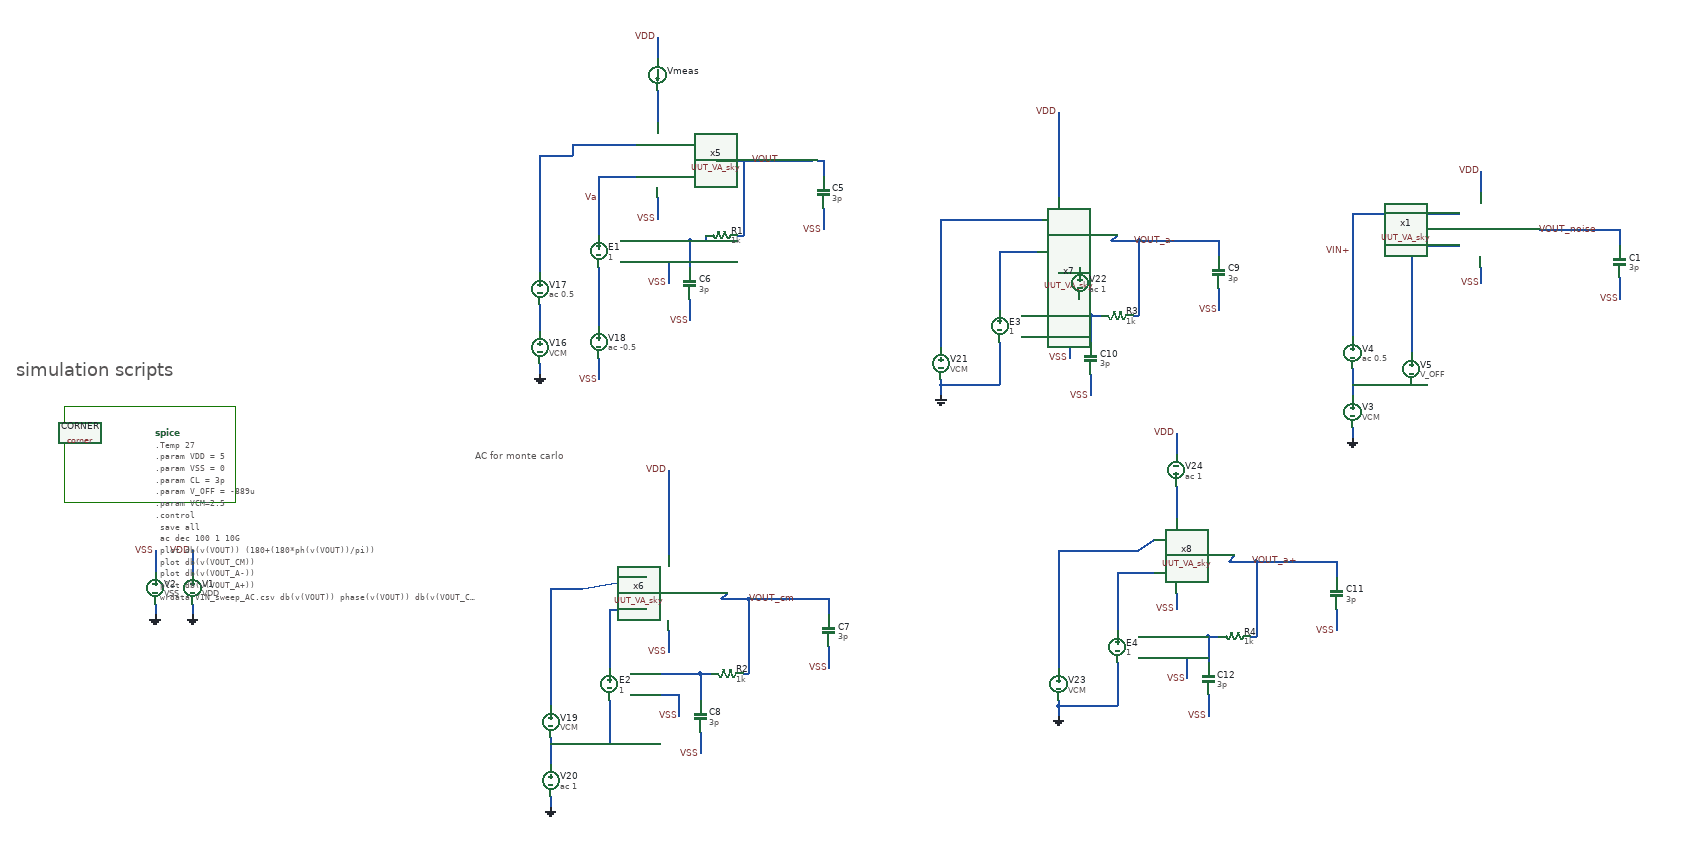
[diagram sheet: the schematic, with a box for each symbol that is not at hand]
v {xschem version=3.4.6 file_version=1.2}
G {}
K {}
V {}
S {}
E {}
L 4 -1660 -1300 -1660 -1140 {}
L 4 -1660 -1140 -1340 -1140 {}
L 4 -1340 -1320 -1340 -1140 {}
L 4 -1660 -1320 -1340 -1320 {}
L 4 -1660 -1320 -1660 -1300 {}
T {simulation scripts} -1750 -1400 0 0 1 1 {}
T {AC for monte carlo} -890 -1240 0 0 0.4 0.4 {}
N -1420 -950 -1420 -930 {
lab=GND}
N -1420 -1050 -1420 -1010 {
lab=VDD}
N -1490 -950 -1490 -930 {
lab=GND}
N -1490 -1050 -1490 -1010 {
lab=VSS}
N -550 -1710 -550 -1670 {
lab=VSS}
N -770 -1510 -770 -1460 {
lab=#net1}
N -550 -2010 -550 -1970 {
lab=VDD}
N -440 -1780 -390 -1780 {
lab=VOUT}
N -550 -1910 -550 -1850 {
lab=#net2}
N -240 -1690 -240 -1650 {
lab=VSS}
N -400 -1780 -260 -1780 {lab=VOUT}
N -250 -1780 -240 -1780 {lab=VOUT}
N -240 -1780 -240 -1750 {lab=VOUT}
N -770 -1790 -710 -1790 {lab=#net3}
N -770 -1400 -770 -1380 {lab=GND}
N -770 -1790 -770 -1570 {lab=#net3}
N -660 -1690 -660 -1640 {lab=Va}
N -660 -1750 -660 -1690 {lab=Va}
N -660 -1410 -660 -1370 {
lab=VSS}
N -660 -1580 -660 -1550 {lab=#net4}
N -390 -1780 -390 -1640 {lab=VOUT}
N -530 -1590 -530 -1550 {
lab=VSS}
N -620 -1590 -530 -1590 {lab=VSS}
N -660 -1500 -660 -1470 {lab=#net4}
N -660 -1550 -660 -1500 {lab=#net4}
N -400 -1640 -390 -1640 {lab=VOUT}
N -490 -1520 -490 -1480 {
lab=VSS}
N -490 -1630 -490 -1580 {lab=#net5}
N -490 -1630 -470 -1630 {lab=#net5}
N -620 -1630 -490 -1630 {lab=#net5}
N -530 -900 -530 -860 {
lab=VSS}
N -750 -700 -750 -650 {
lab=#net6}
N -530 -1200 -530 -1160 {
lab=VDD}
N -430 -960 -380 -960 {
lab=VOUT_cm}
N -530 -1100 -530 -1040 {
lab=VDD}
N -230 -870 -230 -830 {
lab=VSS}
N -240 -960 -230 -960 {lab=VOUT_cm}
N -230 -960 -230 -930 {lab=VOUT_cm}
N -750 -980 -690 -980 {lab=#net7}
N -750 -590 -750 -570 {lab=GND}
N -750 -980 -750 -760 {lab=#net7}
N -640 -880 -640 -830 {lab=#net8}
N -640 -940 -640 -880 {lab=#net8}
N -380 -960 -380 -820 {lab=VOUT_cm}
N -510 -780 -510 -740 {
lab=VSS}
N -600 -780 -510 -780 {lab=VSS}
N -390 -820 -380 -820 {lab=VOUT_cm}
N -470 -710 -470 -670 {
lab=VSS}
N -470 -820 -470 -770 {lab=#net9}
N -470 -820 -450 -820 {lab=#net9}
N -600 -820 -470 -820 {lab=#net9}
N -640 -770 -640 -690 {lab=#net6}
N -750 -690 -640 -690 {lab=#net6}
N -380 -960 -240 -960 {lab=VOUT_cm}
N 200 -1870 200 -1830 {
lab=VDD}
N 300 -1630 350 -1630 {
lab=VOUT_a-}
N 200 -1770 200 -1710 {
lab=VDD}
N 80 -1670 170 -1670 {lab=#net10}
N 500 -1540 500 -1500 {
lab=VSS}
N 490 -1630 500 -1630 {lab=VOUT_a-}
N 500 -1630 500 -1600 {lab=VOUT_a-}
N -20 -1360 -20 -1340 {lab=GND}
N -20 -1650 -20 -1430 {lab=#net10}
N 90 -1550 90 -1500 {lab=#net11}
N 90 -1610 90 -1550 {lab=#net11}
N 350 -1630 350 -1490 {lab=VOUT_a-}
N 220 -1450 220 -1410 {
lab=VSS}
N 130 -1450 220 -1450 {lab=VSS}
N 340 -1490 350 -1490 {lab=VOUT_a-}
N 260 -1380 260 -1340 {
lab=VSS}
N 260 -1490 260 -1440 {lab=#net12}
N 260 -1490 280 -1490 {lab=#net12}
N 130 -1490 260 -1490 {lab=#net12}
N 90 -1440 90 -1360 {lab=GND}
N -20 -1360 90 -1360 {lab=GND}
N 350 -1630 490 -1630 {lab=VOUT_a-}
N -20 -1370 -20 -1360 {lab=GND}
N 240 -1600 240 -1580 {lab=#net13}
N 240 -1520 240 -1510 {lab=VSS}
N 420 -1270 420 -1230 {
lab=VDD}
N 520 -1030 570 -1030 {
lab=VOUT_a+}
N 420 -1170 420 -1110 {
lab=#net14}
N 260 -1050 350 -1050 {lab=#net15}
N 720 -940 720 -900 {
lab=VSS}
N 710 -1030 720 -1030 {lab=VOUT_a+}
N 720 -1030 720 -1000 {lab=VOUT_a+}
N 200 -1050 260 -1050 {lab=#net15}
N 310 -1010 360 -1010 {lab=#net16}
N 200 -760 200 -740 {lab=GND}
N 200 -1050 200 -830 {lab=#net15}
N 310 -950 310 -900 {lab=#net16}
N 310 -1010 310 -950 {lab=#net16}
N 570 -1030 570 -890 {lab=VOUT_a+}
N 440 -850 440 -810 {
lab=VSS}
N 350 -850 440 -850 {lab=VSS}
N 560 -890 570 -890 {lab=VOUT_a+}
N 480 -780 480 -740 {
lab=VSS}
N 480 -890 480 -840 {lab=#net17}
N 480 -890 500 -890 {lab=#net17}
N 350 -890 480 -890 {lab=#net17}
N 310 -840 310 -760 {lab=GND}
N 200 -760 310 -760 {lab=GND}
N 570 -1030 710 -1030 {lab=VOUT_a+}
N 200 -770 200 -760 {lab=GND}
N 420 -970 420 -950 {lab=VSS}
N 420 -950 420 -940 {lab=VSS}
N 200 -1830 200 -1770 {lab=VDD}
N -530 -1160 -530 -1100 {lab=VDD}
N -660 -1750 -590 -1750 {lab=Va}
N -710 -1810 -590 -1810 {lab=#net3}
N -710 -1810 -710 -1790 {lab=#net3}
N -460 -1640 -460 -1630 {lab=#net5}
N -470 -1630 -460 -1630 {lab=#net5}
N -20 -1670 80 -1670 {lab=#net10}
N -20 -1670 -20 -1650 {lab=#net10}
N 90 -1610 160 -1610 {lab=#net11}
N 200 -1570 240 -1600 {lab=#net13}
N 300 -1630 310 -1640 {lab=VOUT_a-}
N 520 -1030 530 -1040 {lab=VOUT_a+}
N 350 -1050 380 -1070 {lab=#net15}
N 360 -1010 380 -1010 {lab=#net16}
N -430 -960 -420 -970 {lab=VOUT_cm}
N -640 -940 -570 -940 {lab=#net8}
N -690 -980 -570 -1000 {lab=#net7}
N 750 -1390 750 -1340 {
lab=#net18}
N 750 -1280 750 -1260 {lab=GND}
N 750 -1670 750 -1450 {lab=VIN+}
N 750 -1680 750 -1670 {lab=VIN+}
N 750 -1680 950 -1680 {lab=VIN+}
N 750 -1360 860 -1360 {lab=#net18}
N 860 -1620 860 -1420 {lab=#net19}
N 860 -1620 950 -1620 {lab=#net19}
N 990 -1580 990 -1560 {lab=VSS}
N 990 -1560 990 -1550 {lab=VSS}
N 990 -1760 990 -1720 {
lab=VDD}
N 1250 -1560 1250 -1520 {
lab=VSS}
N 1240 -1650 1250 -1650 {lab=VOUT_noise}
N 1250 -1650 1250 -1620 {lab=VOUT_noise}
N 1100 -1650 1240 -1650 {lab=VOUT_noise}
C {devices/lab_pin.sym} -1420 -1050 0 0 {name=p6 sig_type=std_logic lab=VDD}
C {devices/vsource.sym} -1420 -980 0 0 {name=V1 value="VDD"

}
C {devices/gnd.sym} -1420 -930 0 0 {name=l3 lab=GND}
C {devices/vsource.sym} -1490 -980 0 0 {name=V2 value="VSS"


}
C {devices/gnd.sym} -1490 -930 0 0 {name=l1 lab=GND}
C {sky130_fd_pr/corner.sym} -1630 -1270 0 0 {name=CORNER only_toplevel=true corner=tt}
C {devices/lab_pin.sym} -1490 -1050 0 0 {name=p8 sig_type=std_logic lab=VSS
}
C {devices/code.sym} -1490 -1270 0 0 {name=spice only_toplevel=false
format="tcleval( @value )"
value="	
.Temp 27
.param VDD = 5
.param VSS = 0
.param CL = 3p
.param V_OFF = -889u
.param VCM=2.5


.control

	save all
	ac dec 100 1 10G
	plot db(v(VOUT)) (180+(180*ph(v(VOUT))/pi))
	plot db(v(VOUT_CM))
	plot db(v(VOUT_A-))
	plot db(v(VOUT_A+))	
	wrdata VIN_sweep_AC.csv db(v(VOUT)) phase(v(VOUT)) db(v(VOUT_CM)) db(v(VOUT_A-)) db(v(VOUT_A+))

	noise v(VOUT_noise,VSS) V4 dec 10 1 40000k
	print inoise_total 
	print onoise_total
	setplot noise1

	plot onoise_spectrum
	plot inoise_spectrum

.endc



"}
C {devices/lab_pin.sym} -550 -1670 0 0 {name=p23 sig_type=std_logic lab=VSS
}
C {devices/lab_pin.sym} -550 -2010 0 0 {name=p24 sig_type=std_logic lab=VDD}
C {ammeter.sym} -550 -1940 0 0 {name=Vmeas savecurrent=true}
C {Sky130A/UUT_sky/UUT_VA_sky.sym} -520 -1780 0 0 {name=x5}
C {capa.sym} -240 -1720 0 0 {name=C5
m=1
value=3p
footprint=1206
device="ceramic capacitor"}
C {devices/lab_pin.sym} -240 -1650 0 0 {name=p26 sig_type=std_logic lab=VSS
}
C {devices/vsource.sym} -770 -1430 0 0 {name=V16 value= "VCM"}
C {devices/gnd.sym} -770 -1380 0 0 {name=l7 lab=GND}
C {devices/vsource.sym} -770 -1540 0 0 {name=V17 value= "ac 0.5"}
C {devices/lab_pin.sym} 750 -1610 0 0 {name=p27 sig_type=std_logic lab=VIN+
}
C {devices/lab_pin.sym} -660 -1370 0 0 {name=p28 sig_type=std_logic lab=VSS
}
C {devices/vsource.sym} -660 -1440 0 0 {name=V18 value= "ac -0.5"}
C {vcvs.sym} -660 -1610 0 1 {name=E1 value=1}
C {devices/lab_pin.sym} -530 -1550 0 0 {name=p29 sig_type=std_logic lab=VSS
}
C {devices/lab_pin.sym} -660 -1710 0 0 {name=p30 sig_type=std_logic lab=Va
}
C {res_ac.sym} -430 -1640 1 0 {name=R1
value=1k
ac=1000000000000G
m=1}
C {capa.sym} -490 -1550 0 0 {name=C6
m=1
value=3p
footprint=1206
device="ceramic capacitor"}
C {devices/lab_pin.sym} -490 -1480 0 0 {name=p31 sig_type=std_logic lab=VSS
}
C {devices/lab_pin.sym} -530 -860 0 0 {name=p32 sig_type=std_logic lab=VSS
}
C {devices/lab_pin.sym} -530 -1200 0 0 {name=p33 sig_type=std_logic lab=VDD}
C {Sky130A/UUT_sky/UUT_VA_sky.sym} -500 -970 0 0 {name=x6}
C {capa.sym} -230 -900 0 0 {name=C7
m=1
value=3p
footprint=1206
device="ceramic capacitor"}
C {devices/lab_pin.sym} -230 -830 0 0 {name=p34 sig_type=std_logic lab=VSS
}
C {devices/vsource.sym} -750 -730 0 0 {name=V19 value= "VCM"}
C {devices/gnd.sym} -750 -570 0 0 {name=l8 lab=GND}
C {devices/vsource.sym} -750 -620 0 0 {name=V20 value= "ac 1"}
C {vcvs.sym} -640 -800 0 1 {name=E2 value=1}
C {devices/lab_pin.sym} -510 -740 0 0 {name=p35 sig_type=std_logic lab=VSS
}
C {res_ac.sym} -420 -820 1 0 {name=R2
value=1k
ac=1000000000000G
m=1}
C {capa.sym} -470 -740 0 0 {name=C8
m=1
value=3p
footprint=1206
device="ceramic capacitor"}
C {devices/lab_pin.sym} -470 -670 0 0 {name=p36 sig_type=std_logic lab=VSS
}
C {devices/lab_pin.sym} 240 -1510 0 0 {name=p38 sig_type=std_logic lab=VSS
}
C {devices/lab_pin.sym} 200 -1870 0 0 {name=p39 sig_type=std_logic lab=VDD}
C {Sky130A/UUT_sky/UUT_VA_sky.sym} 230 -1640 0 0 {name=x7}
C {capa.sym} 500 -1570 0 0 {name=C9
m=1
value=3p
footprint=1206
device="ceramic capacitor"}
C {devices/lab_pin.sym} 500 -1500 0 0 {name=p40 sig_type=std_logic lab=VSS
}
C {devices/vsource.sym} -20 -1400 0 0 {name=V21 value= "VCM"}
C {devices/gnd.sym} -20 -1340 0 0 {name=l9 lab=GND}
C {vcvs.sym} 90 -1470 0 1 {name=E3 value=1}
C {devices/lab_pin.sym} 220 -1410 0 0 {name=p41 sig_type=std_logic lab=VSS
}
C {res_ac.sym} 310 -1490 1 0 {name=R3
value=1k
ac=1000000000000G
m=1}
C {capa.sym} 260 -1410 0 0 {name=C10
m=1
value=3p
footprint=1206
device="ceramic capacitor"}
C {devices/lab_pin.sym} 260 -1340 0 0 {name=p42 sig_type=std_logic lab=VSS
}
C {devices/vsource.sym} 240 -1550 0 0 {name=V22 value= "ac 1"}
C {devices/lab_pin.sym} 420 -940 0 0 {name=p44 sig_type=std_logic lab=VSS
}
C {devices/lab_pin.sym} 420 -1270 0 0 {name=p45 sig_type=std_logic lab=VDD}
C {Sky130A/UUT_sky/UUT_VA_sky.sym} 450 -1040 0 0 {name=x8}
C {capa.sym} 720 -970 0 0 {name=C11
m=1
value=3p
footprint=1206
device="ceramic capacitor"}
C {devices/lab_pin.sym} 720 -900 0 0 {name=p46 sig_type=std_logic lab=VSS
}
C {devices/vsource.sym} 200 -800 0 0 {name=V23 value= "VCM"}
C {devices/gnd.sym} 200 -740 0 0 {name=l10 lab=GND}
C {vcvs.sym} 310 -870 0 1 {name=E4 value=1}
C {devices/lab_pin.sym} 440 -810 0 0 {name=p47 sig_type=std_logic lab=VSS
}
C {res_ac.sym} 530 -890 1 0 {name=R4
value=1k
ac=1000000000000G
m=1}
C {capa.sym} 480 -810 0 0 {name=C12
m=1
value=3p
footprint=1206
device="ceramic capacitor"}
C {devices/lab_pin.sym} 480 -740 0 0 {name=p48 sig_type=std_logic lab=VSS
}
C {devices/vsource.sym} 420 -1200 2 0 {name=V24 value= "ac 1"}
C {devices/lab_pin.sym} 650 -1030 1 0 {name=p49 sig_type=std_logic lab=VOUT_a+

}
C {devices/lab_pin.sym} 420 -1630 1 0 {name=p43 sig_type=std_logic lab=VOUT_a-

}
C {devices/lab_pin.sym} -290 -960 1 0 {name=p37 sig_type=std_logic lab=VOUT_cm

}
C {devices/lab_pin.sym} -320 -1780 1 0 {name=p25 sig_type=std_logic lab=VOUT
}
C {Sky130A/UUT_sky/UUT_VA_sky.sym} 1020 -1650 0 0 {name=x1}
C {devices/vsource.sym} 750 -1310 0 0 {name=V3 value= "VCM"}
C {devices/gnd.sym} 750 -1260 0 0 {name=l2 lab=GND}
C {devices/vsource.sym} 750 -1420 0 0 {name=V4 value= "ac 0.5"}
C {devices/vsource.sym} 860 -1390 0 0 {name=V5 value= "V_OFF"}
C {devices/lab_pin.sym} 990 -1550 0 0 {name=p2 sig_type=std_logic lab=VSS
}
C {devices/lab_pin.sym} 990 -1760 0 0 {name=p3 sig_type=std_logic lab=VDD}
C {capa.sym} 1250 -1590 0 0 {name=C1
m=1
value=3p
footprint=1206
device="ceramic capacitor"}
C {devices/lab_pin.sym} 1250 -1520 0 0 {name=p4 sig_type=std_logic lab=VSS
}
C {devices/lab_pin.sym} 1210 -1650 1 0 {name=p5 sig_type=std_logic lab=VOUT_noise

}
